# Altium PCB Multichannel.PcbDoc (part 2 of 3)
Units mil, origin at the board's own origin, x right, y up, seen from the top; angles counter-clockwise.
Board outline 3858.27 x 3228.35 mil, 2 copper layers (Top Layer, Bottom Layer); 95 components, 49 nets, 285 pads, 121 vias.

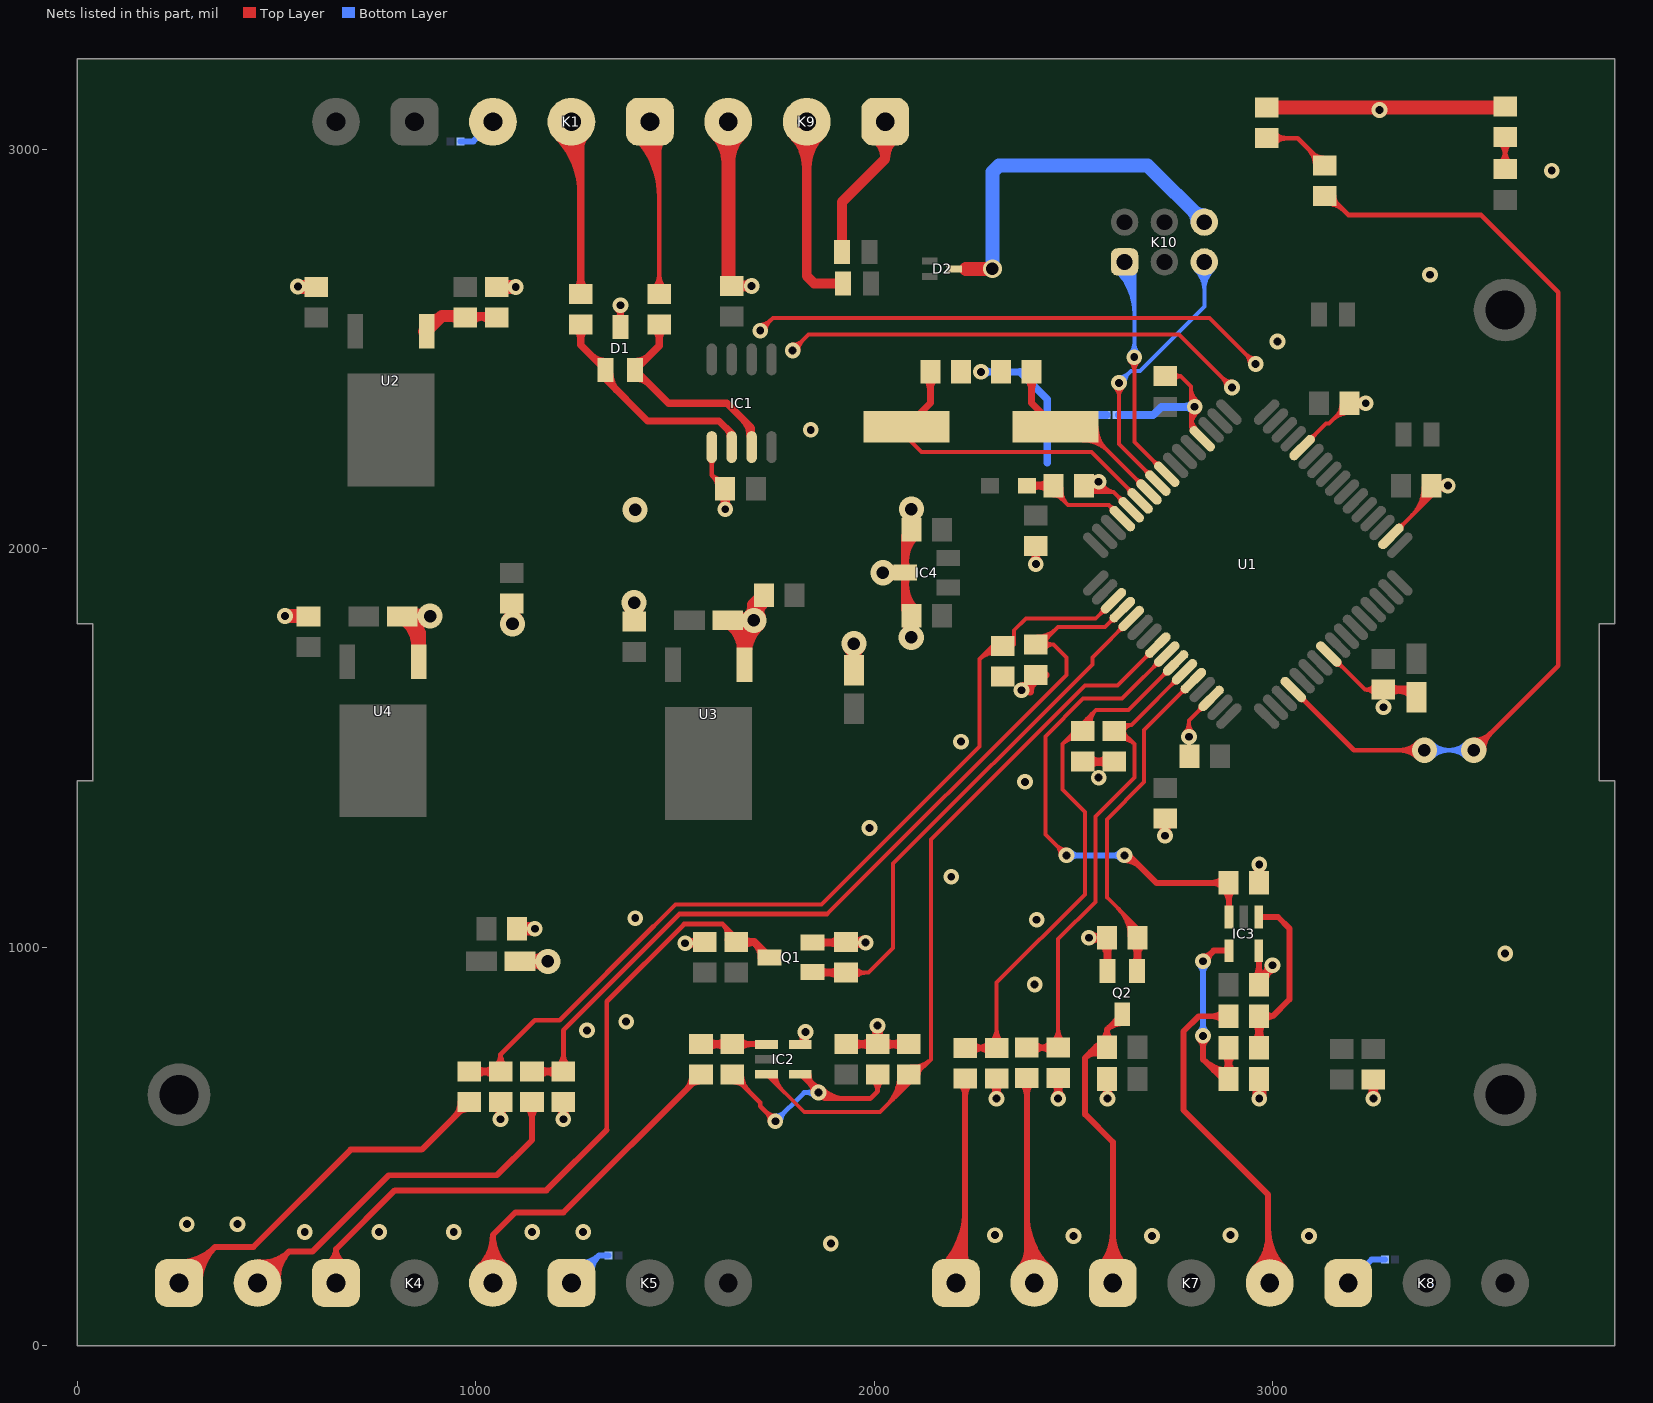
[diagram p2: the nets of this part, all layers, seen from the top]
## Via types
v1: diameter 39.37, hole 19.68, Top Layer to Bottom Layer, 99 vias
v2: diameter 62.99, hole 31.5, Top Layer to Bottom Layer, 21 vias
v3: diameter 47.24, hole 31.5, Top Layer to Bottom Layer, 1 vias

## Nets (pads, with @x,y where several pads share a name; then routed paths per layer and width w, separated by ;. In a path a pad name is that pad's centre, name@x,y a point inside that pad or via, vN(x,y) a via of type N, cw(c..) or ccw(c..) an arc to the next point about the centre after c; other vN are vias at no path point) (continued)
GND: C1.2 C2.2 C3.2 C4.2 C5.2 C6.2 C7.2 C8.2 C9.2 C10.2 C11.2 C12.2 C13.2 C14.2 C15.2 C16.2 C17.2 C18.2 C19.2 C20.2 C21.2 C22.2 C24.2 C26.2 C27.2 C28.2 C29.2 C30.2 C31.2 C32.2 D1.3 D2.3 IC1.5 IC2.5 IC3.5 IC4.3 K1.3 K5.1 K8.1 K9.3 K10.6 LED1.K LED2.K NT1.2 NT2.2 NT3.2 NT4.2 Q1.S Q2.S R4.1 R6.1 R8.1 R10.1 R14.1 R15.1 R16.1 R19.2 R20.1 R23.2 R26.2 R27.2 R29.2 U1.14 U1.24 U1.34 U1.44 U1.52 U1.60 U3.1 U4.1 | length 16822.6
  Top Layer w10: D1.3@1352.62,2576.98 ccw(c1327.02,2602.59) 1363.23,2602.59 ccw(c1399.44,2602.59) D1.3@1373.84,2576.98 ; v1@1352.85,2600.26 cw(c1327.78,2575.19) 1363.23,2575.19 cw(c1398.68,2575.19) v1@1373.61,2600.26 ; v1@1355.32,2598.27 cw(c1350.28,2590.39) 1359.31,2587.97 cw(c1371.34,2584.75) v1@1367.62,2596.63 ; v1@1358.84,2596.63 cw(c1355.12,2584.75) 1367.15,2587.97 cw(c1376.18,2590.39) v1@1371.14,2598.27 ; D1.3@1363.23,2556.38 v1(1363.23,2610.64) ; v1(1713.86,2546.82) 1746.09,2579.04 2840.7,2579.04 v1(2956.73,2463.01) ; v1@1713.86,2561.5 ccw(c1713.86,2596.96) 1738.93,2571.89 ccw(c1764,2546.82) v1@1728.54,2546.82 ; v1(1795.32,2496.82) 1835.54,2537.04 2764.59,2537.04 v1(2897.68,2403.95) ; v1@1795.32,2511.5 ccw(c1795.32,2546.96) 1820.39,2521.89 ccw(c1845.45,2496.82) v1@1810,2496.82 ; v2(2021.69,1939.47) IC4.3@2077.69,1939.47 ; v2@2034.45,1929.01 cw(c2056.56,1910.87) 2056.56,1939.47 cw(c2056.56,1968.06) v2@2034.45,1949.93 ; v2@2042.18,1922.66 cw(c2077.69,1893.54) IC4.3@2077.69,1939.47 ; v2@2042.18,1956.27 ccw(c2077.69,1985.39) IC4.3@2077.69,1939.47 ; IC4.3@2057.09,1928.86 ccw(c2031.48,1903.25) 2031.48,1939.47 ccw(c2031.48,1975.68) IC4.3@2057.09,1950.07 ; v2@2076.03,1797.64 ccw(c2050.67,1828.48) C11.2@2090.59,1828.48 ; C12.2@2078.04,2077.18 cw(c2057.29,2047.74) C12.2@2093.31,2047.73 ; C11.2@2079.1,1812.56 cw(c2051.35,1784.81) v2@2090.59,1784.81 ; C12.2@2079.5,2066.77 ccw(c2049.18,2098.83) v2(2093.31,2098.83) ; v2@2083.8,2085.35 cw(c2070.88,2067.02) 2093.31,2067.02 cw(c2115.73,2067.02) v2@2102.81,2085.35 ; v2@2090.59,1779.36 cw(c2131.15,1779.36) C11.2@2105.85,1811.06 ; v2@2090.59,1800.14 cw(c2114.56,1800.14) C11.2@2099.61,1818.88 ; C11.2@2090.59,1810.64 ccw(c2113.32,1810.64) v2@2101.46,1791.25 ; v2(2092.86,1777.18) 2090.59,1779.44 C11.2@2090.59,1828.48 ; C11.2@2093.31,1831.2 C11.2@2090.59,1828.48 ; v2@2094.3,2098.83 v2(2093.31,2098.83) ; v2@2106.68,1799.78 cw(c2124.24,1828.48) C11.2@2090.59,1828.48 ; C12.2@2107.12,2066.77 cw(c2137.44,2098.83) v2(2093.31,2098.83) ; C12.2@2108.57,2077.18 ccw(c2129.33,2047.74) C12.2@2093.31,2047.73 ; R26.2@2292.62,656.06 cw(c2258.31,621.75) 2306.84,621.75 cw(c2355.36,621.75) R26.2@2321.05,656.06 ; v1@2296.45,630.46 ccw(c2271.38,655.53) 2306.84,655.53 ccw(c2342.29,655.53) v1@2317.22,630.46 ; v1@2296.52,630.53 ccw(c2285.85,641.35) 2300.53,645.29 ccw(c2316.11,649.46) v1@2311.25,634.08 ; v1@2302.42,634.08 ccw(c2297.56,649.46) 2313.14,645.29 ccw(c2327.82,641.35) v1@2317.15,630.53 ; v1(2306.84,620.08) R26.2@2306.84,670.28 ; C1.2@2391.82,1991.02 cw(c2365.96,1961.04) v1(2405.55,1961.04) ; C1.2@2394.73,1996.01 C1.2@2404.95,2006.23 2405.55,2005.63 v1(2405.55,1961.04) ; v1@2395.17,1971.42 ccw(c2370.1,1996.49) 2405.55,1996.49 ccw(c2441.01,1996.49) v1@2415.94,1971.42 ; v1@2397.4,1973.25 ccw(c2393.53,1979.03) 2400.25,1980.83 ccw(c2406.96,1982.63) v1@2406.51,1975.69 ; v1@2403.77,1975.61 ccw(c2402.7,1984.34) 2411.19,1982.06 ccw(c2419.67,1979.79) v1@2414.39,1972.77 ; C1.2@2418.74,1991.62 ccw(c2447.6,1961.04) v1(2405.55,1961.04) ; R29.2@2447.15,657.05 cw(c2412.84,622.74) 2461.36,622.74 cw(c2509.88,622.74) R29.2@2475.57,657.05 ; v1@2450.98,630.46 ccw(c2425.91,655.53) 2461.36,655.53 ccw(c2496.82,655.53) v1@2471.75,630.46 ; v1@2451.02,630.51 ccw(c2439.88,641.75) 2455.17,645.85 ccw(c2471.96,650.35) v1@2466.22,633.94 ; v1@2456.51,633.94 ccw(c2450.76,650.35) 2467.55,645.85 ccw(c2482.84,641.75) v1@2471.7,630.51 ; v1(2461.36,620.08) R29.2@2461.36,671.26 ; C20.2@2526.04,2153.53 ccw(c2553.17,2179.65) 2553.17,2141.99 ; C20.2@2532.34,2164.26 C20.2@2525.97,2157.89 2541.86,2141.99 2600.2,2141.99 ; C20.2@2533.24,2160.46 ccw(c2576.68,2202.3) 2576.68,2141.99 ; C20.2@2540.44,2167.4 ccw(c2600.19,2224.95) 2600.19,2141.99 ; C20.2@2547.95,2164.89 ccw(c2573.46,2169.71) 2566.8,2144.61 ; v1@2558.14,2165.57 ccw(c2586.62,2178.26) 2577.62,2148.41 ; v1@2567.28,2169.64 ccw(c2612.99,2190.01) 2598.53,2142.1 ; C30.2@2571.22,649.19 cw(c2547.83,620.06) v1(2585.19,620.08) cw(c2628.08,620.06) C30.2@2597.93,650.57 ; v1@2574.81,630.46 ccw(c2549.74,655.53) 2585.19,655.53 ccw(c2620.64,655.53) v1@2595.57,630.46 ; v1@2583.15,634.62 ccw(c2581.85,643.94) 2590.94,641.51 ccw(c2600.03,639.07) v1@2594.23,631.65 ; C30.2@2583.8,669.29 2585.19,667.91 v1(2585.19,620.08) ; U1.60@2617.75,2117.63 ccw(c2601.3,2117.63) 2612.93,2129.26 ccw(c2624.56,2140.89) U1.60@2624.56,2124.44 ; U1.60@2644.74,2097.45 2600.2,2141.99 ; C16.2@2730.36,2432.49 2768.15,2432.49 ; C16.2@2752.55,2423.1 cw(c2768.15,2414.85) 2768.15,2432.49 ; C16.2@2752.55,2441.89 ccw(c2768.15,2450.14) 2768.15,2432.49 ; v1@2779.03,1538.35 ccw(c2753.96,1563.42) 2789.41,1563.42 ccw(c2824.86,1563.42) v1@2799.79,1538.35 ; v1(2789.41,1527.97) 2789.41,1568.42 U1.14@2845.18,1624.19 ; 2794.36,2304.66 cw(c2845.89,2304.66) v1@2813.08,2344.4 ; 2794.36,2308.31 ccw(c2815.23,2308.31) U1.52@2800.47,2293.55 ; 2794.36,2325.89 cw(c2828.37,2325.89) v1@2806.71,2352.11 ; 2794.36,2332.45 ccw(c2839.37,2332.45) U1.52@2807.54,2300.62 ; 2794.36,2385.27 ccw(c2827.75,2385.27) v1@2806.68,2359.36 ; U1.52@2796.23,2297.85 ccw(c2788.98,2300.15) 2794.36,2305.53 ; U1.52@2802.23,2302.59 cw(c2801.5,2312.67) 2794.36,2305.53 ; v1@2812.99,2367.12 cw(c2844.84,2406.29) 2794.36,2406.29 ; U1.14@2818.19,1604 cw(c2801.74,1604) 2813.37,1592.38 cw(c2825,1580.75) U1.14@2825,1597.19 ; U1.52@2824.3,2274.23 2824.3,2275.58 2794.36,2305.53 ; v1@2882.99,2403.95 ccw(c2847.54,2403.95) 2872.61,2429.02 ccw(c2897.68,2454.09) v1@2897.68,2418.64 ; v1@2942.05,2463.01 ccw(c2906.6,2463.01) 2931.66,2488.08 ccw(c2956.73,2513.14) v1@2956.73,2477.69 ; U1.44@3073.46,2253.35 3133.61,2313.5 3140.88,2313.5 C17.2@3191.97,2364.58 v1(3233,2364.58) ; U1.44@3093.64,2280.34 ccw(c3093.64,2296.78) 3105.27,2285.16 ccw(c3116.9,2273.53) U1.44@3100.45,2273.53 ; U1.24@3140.27,1735.54 3141.87,1735.54 3231.34,1646.08 ; 3150.1,2322.71 cw(c3191.97,2280.84) C17.2@3191.97,2340.05 ; U1.24@3160.46,1708.55 cw(c3160.46,1688.24) 3174.82,1702.6 ; 3160.79,2333.4 ccw(c3134.04,2360.15) C17.2@3171.87,2360.15 ; C17.2@3167.17,2339.78 cw(c3191.97,2314.98) C17.2@3191.97,2350.05 ; U1.24@3167.27,1715.36 ccw(c3179.84,1715.36) 3170.95,1706.47 ; C17.2@3207.85,2352.26 cw(c3233,2332.75) v1(3233,2364.58) ; C17.2@3207.85,2376.9 ccw(c3233,2396.41) v1(3233,2364.58) ; v1@3222.62,2354.2 ccw(c3197.55,2329.13) 3197.55,2364.58 ccw(c3197.55,2400.03) v1@3222.62,2374.97 ; C19.2@3256.06,1633.87 ccw(c3231.34,1614.96) 3231.34,1646.08 ; C19.2@3256.06,1658.29 cw(c3231.34,1677.2) 3231.34,1646.08 ; C19.2@3276.45,1646.08 3231.34,1646.08 ; U1.34@3296.17,2030.64 3296.46,2030.64 3397.93,2132.11 C15.2@3397.93,2157.89 v1(3439.02,2157.89) ; U1.34@3316.35,2057.63 ccw(c3316.35,2074.77) 3328.47,2062.65 ; U1.34@3323.16,2050.82 cw(c3338.91,2050.82) 3327.78,2061.95 ; 3348.52,2082.7 ccw(c3277.76,2153.46) C15.2@3377.83,2153.46 ; 3365.59,2099.77 ccw(c3311.9,2153.46) C15.2@3387.83,2153.46 ; 3382.66,2116.84 ccw(c3346.04,2153.46) C15.2@3397.83,2153.46 ; C15.2@3413.8,2145.55 cw(c3439.02,2125.94) v1(3439.02,2157.89) ; C15.2@3413.8,2170.22 ccw(c3439.02,2189.83) v1(3439.02,2157.89) ; v1@3428.63,2147.5 ccw(c3403.56,2122.44) 3403.56,2157.89 ccw(c3403.56,2193.34) v1@3428.63,2168.27 ; C12.2@2093.31,2047.73 v2(2093.31,2098.83) ; 2768.15,2432.49 2794.36,2406.29 ; 2794.36,2305.53 2794.36,2406.29
  Top Layer w12: IC1.5@1587.41,2222.63 cw(c1575.46,2210.68) 1592.36,2210.68 cw(c1609.26,2210.68) IC1.5@1597.31,2222.63 ; IC1.5@1592.36,2254.58 1592.36,2183.91 ; 1596.7,2179.57 cw(c1571.66,2154.53) C26.2@1607.07,2154.53 ; C26.2@1612.67,2132.17 cw(c1580.06,2099.56) 1626.17,2099.56 cw(c1672.28,2099.56) C26.2@1639.67,2132.17 ; v1@1616.42,2108.44 ccw(c1606.14,2118.56) 1620.08,2122.3 ccw(c1634.41,2126.14) v1@1630.12,2111.93 ; v1@1616.49,2108.51 ccw(c1593.13,2131.87) 1626.17,2131.87 ccw(c1659.21,2131.87) v1@1635.85,2108.51 ; v1@1622.22,2111.93 ccw(c1617.93,2126.14) 1632.26,2122.3 ccw(c1646.2,2118.56) v1@1635.92,2108.44 ; C26.2@1623.54,2173.45 cw(c1618.46,2210) 1592.37,2183.9 ; v1(1626.17,2098.83) C26.2@1626.17,2150.1 1592.36,2183.91
  Top Layer w15: R19.2@1050.15,598.78 cw(c1020.11,568.73) 1062.6,568.73 cw(c1105.09,568.73) R19.2@1075.04,598.78 ; v1@1053.68,576.59 ccw(c1043.4,586.15) 1056.96,589.78 ccw(c1070.78,593.49) v1@1066.36,579.88 ; v1@1053.98,576.91 ccw(c1033.18,597.71) 1062.6,597.71 ccw(c1092.02,597.71) v1@1071.21,576.91 ; v1@1058.84,579.88 ccw(c1054.42,593.49) 1068.24,589.78 ccw(c1081.8,586.15) v1@1071.52,576.59 ; v1(1062.6,568.29) R19.2@1062.6,611.22 ; R23.2@1207.64,598.78 cw(c1177.59,568.73) 1220.08,568.73 cw(c1262.57,568.73) R23.2@1232.52,598.78 ; v1@1211.16,576.59 ccw(c1200.88,586.15) 1214.44,589.78 ccw(c1228.26,593.49) v1@1223.84,579.88 ; v1@1211.46,576.91 ccw(c1190.66,597.71) 1220.08,597.71 ccw(c1249.5,597.71) v1@1228.7,576.91 ; v1@1216.32,579.88 ccw(c1211.9,593.49) 1225.72,589.78 ccw(c1239.28,586.15) v1@1229,576.59 ; v1(1220.08,568.29) R23.2@1220.08,611.22 ; v1@1534.08,1018.58 ccw(c1543.01,1027.78) 1546.33,1015.4 ccw(c1549.64,1003.02) v1@1537.31,1006.52 ; v1@1534.21,1001.23 cw(c1555.01,980.43) 1555.01,1009.84 cw(c1555.01,1039.26) v1@1534.21,1018.46 ; v1@1535.02,1009.84 cw(c1535.02,977.44) C29.2@1557.93,1000.35 ; v1@1535.33,1002.52 cw(c1544.25,995.82) 1547.14,1006.59 cw(c1551.47,1022.77) v1@1536.49,1015.29 ; C29.2@1557.03,1024.27 cw(c1525.59,1051.31) v1(1525.59,1009.84) 1571.85,1009.84 C29.2@1574.8,1012.8 ; v1@1817.13,780.87 cw(c1800.17,770.11) IC2.5@1814.37,755.91 v1@1827.42,768.95 ; v1@1827.42,775.21 ccw(c1851.39,775.21) IC2.5@1834.44,758.26 ; v1(1827.42,787.4) v1@1827.42,768.95 ; IC2.5@1833.6,758.87 cw(c1838.73,768.95) v1@1827.42,768.95 ; C21.2@2523.27,1465.17 C21.2@2523.27,1465.76 ; v1(2538.43,1023.62) R20.1@2583.8,1023.62 ; v1@2546.69,1014.66 cw(c2557.27,1003.19) 2561.31,1018.27 cw(c2565.88,1035.31) v1@2549.64,1028.4 ; v1@2546.69,1032.58 ccw(c2557.27,1044.06) 2561.31,1028.98 ccw(c2565.88,1011.93) v1@2549.64,1018.85 ; v1@2547.04,1015.01 cw(c2567.84,994.2) 2567.84,1023.62 cw(c2567.84,1053.04) v1@2547.04,1032.24 ; R20.1@2571.36,1011.18 ccw(c2541.32,981.14) 2541.32,1023.62 ccw(c2541.32,1066.11) R20.1@2571.36,1036.07 ; C28.2@2953.25,922.39 ccw(c2925.58,950.05) 2964.71,950.05 ; R10.1@2953.42,1178.46 ccw(c2925.12,1207.53) v1(2965.69,1207.54) ; v1@2962.59,1195.75 cw(c2959.53,1184.14) 2971.13,1187.25 cw(c2982.73,1190.36) v1@2974.27,1198.88 ; v1@2962.6,1210.63 v1(2965.69,1207.54) ; 2964.71,954.8 ccw(c3010.56,954.8) C28.2@2978.14,922.39 ; IC3.5@2964.71,991.14 2964.71,906.5 C28.2@2965.69,905.51 2965.69,921.34 v1(2999.08,954.72) ccw(c3037.8,916) C28.2@2983.23,911.41 ; R10.1@2965.69,1161.42 v1(2965.69,1207.54) ; v1@2968.8,1195.75 ccw(c2971.86,1184.14) 2960.26,1187.25 ccw(c2948.66,1190.36) 2957.11,1198.88 cw(c2936.28,1178.12) 2965.69,1178.12 cw(c2995.11,1178.12) v1@2974.31,1198.92 ; R10.1@2977.97,1178.46 cw(c3006.27,1207.53) v1(2965.69,1207.54) ; v1@2986.89,954.72 cw(c2957.48,954.72) 2978.28,933.92 cw(c2999.08,913.12) v1@2999.08,942.54 ; v1@2987.4,951.26 cw(c2961.62,943.62) 2984.9,930.17 cw(c3008.18,916.73) v1@3001.92,942.88 ; R27.2@3239.67,655.47 cw(c3209.48,625.29) v1@3252.17,625.29 ; v1@3243.15,628.27 ccw(c3230.35,639.9) 3247.05,644.37 ccw(c3267.91,649.96) v1@3257.85,630.86 ; v1@3243.55,628.69 ccw(c3222.75,649.5) 3252.17,649.5 ccw(c3281.59,649.5) v1@3260.79,628.69 ; v1@3246.46,630.84 ccw(c3236.33,649.93) 3257.2,644.33 ccw(c3273.71,639.91) v1@3261.13,628.33 ; v1(3252.17,620.08) R27.2@3252.17,667.86 ; v1@3252.17,625.57 cw(c3294.45,625.57) R27.2@3264.55,655.47
  Top Layer w19.68: v1@2369.5,1654.46 ccw(c2369.5,1686.58) C14.2@2392.21,1663.87 ; v1@2370.16,1654.44 ccw(c2371.9,1680.51) C14.2@2390.38,1662.03 ; 2390.38,1640.84 cw(c2421.91,1640.84) C14.2@2407.49,1668.88 ; 2390.38,1642.09 C14.2@2390.38,1662.03 ; C14.2@2429.36,1682.45 2410.79,1682.45 C14.2@2390.38,1662.03
  Top Layer w20: R6.1@1642.36,2658.87 v1(1692.36,2658.87) ; R6.1@1657.47,2648.2 cw(c1683.24,2622.42) 1683.24,2658.87 cw(c1683.24,2695.32) R6.1@1657.47,2669.55 ; R6.1@1668.97,2655.05 cw(c1674,2636.28) v1@1686.26,2651.36 ; R6.1@1668.97,2662.7 ccw(c1674,2681.47) v1@1686.26,2666.39 ; v1@1685.52,2652.02 ccw(c1668.98,2635.49) 1668.98,2658.87 ccw(c1668.98,2682.25) v1@1685.52,2665.72 ; Q1.S@1845.34,1011.41 v1(1978.35,1011.41) ; Q1.S@1862.41,1004.34 cw(c1879.48,987.27) 1879.48,1011.41 cw(c1879.48,1035.55) Q1.S@1862.41,1018.48 ; 1884.91,1011.41 ccw(c1884.91,1052.59) R16.1@1914.03,1023.47 ; 1891.6,1011.41 cw(c1891.6,979.69) R16.1@1914.03,1002.12 ; C27.2@1929.53,756.89 R8.1@2008.27,756.89 ; R16.1@1944.24,1002.12 cw(c1966.67,979.69) v1@1966.67,1011.41 ; R16.1@1944.24,1023.47 ccw(c1973.36,1052.59) v1@1973.36,1011.41 ; C27.2@1944.63,746.21 cw(c1970.41,720.44) 1970.41,756.89 cw(c1970.41,793.34) C27.2@1944.63,767.57 ; R16.1@1954.93,1016.35 ccw(c1960.58,1037.42) v1@1972.88,1019.41 ; R16.1@1955.87,1008.52 cw(c1960.14,992.56) v1@1971.62,1004.44 ; R16.1@1958.44,1015.41 cw(c1953.53,997.08) v1@1969.96,1006.57 ; v1@1971.5,1004.56 ccw(c1954.96,988.03) 1954.96,1011.41 ccw(c1954.96,1034.79) v1@1971.5,1018.26 ; R8.1@1993.16,746.21 ccw(c1967.39,720.44) 1967.39,756.89 ccw(c1967.39,793.34) R8.1@1993.16,767.57 ; R8.1@1997.59,767.57 ccw(c1971.82,793.34) 2008.27,793.34 ccw(c2044.72,793.34) R8.1@2018.94,767.57 ; v1@2000.75,797.18 cw(c1985.25,784.59) R8.1@2004.54,779.42 ; v1@2001.42,796.43 cw(c1984.89,779.9) 2008.27,779.9 cw(c2031.65,779.9) v1@2015.12,796.43 ; v1(2008.27,803.28) R8.1@2008.27,756.89 ; R8.1@2012,779.42 cw(c2031.28,784.59) v1@2015.79,797.18 ; R8.1@2023.37,746.21 cw(c2049.15,720.44) 2049.15,756.89 cw(c2049.15,793.34) R8.1@2023.37,767.57 ; IC4.3@2070.62,1932.4 cw(c2053.55,1915.32) 2077.69,1915.32 cw(c2101.84,1915.32) IC4.3@2084.77,1932.4 ; IC4.3@2070.62,1946.54 ccw(c2053.55,1963.61) 2077.69,1963.61 ccw(c2101.84,1963.61) IC4.3@2084.77,1946.54 ; R4.1@2071.9,746.21 ccw(c2046.13,720.44) 2046.13,756.89 ccw(c2046.13,793.34) R4.1@2071.9,767.57 ; 2077.69,1861.49 ccw(c2119.17,1861.49) C11.2@2089.84,1832.16 ; 2077.69,1909.77 ccw(c2167.46,1909.77) C11.2@2103.98,1846.3 ; 2077.69,1969.16 cw(c2167.46,1969.16) C12.2@2103.98,2032.63 ; 2077.69,2017.44 cw(c2119.17,2017.44) C12.2@2089.84,2046.77 ; R4.1@2087.01,756.89 R8.1@2008.27,756.89 ; C11.2@2093.31,1831.2 2077.69,1846.81 IC4.3@2077.69,1939.47 2077.69,2032.12 C12.2@2093.31,2047.73 ; C21.2@2523.27,1465.17 2523.66,1464.78 2601.03,1464.78 C24.2@2602.01,1465.76 ; C20.2@2536.64,2172.99 ccw(c2557.72,2194.07) v1@2557.72,2164.26 ; C20.2@2538.16,2153.41 cw(c2559.53,2137.79) v1@2559.53,2164.26 ; C21.2@2538.37,1455.09 cw(c2561.77,1431.69) 2561.77,1464.78 ; C21.2@2538.37,1476.44 ccw(c2566.53,1504.59) 2566.53,1464.78 ; v1@2555.98,2174.4 cw(c2532.34,2196.88) 2532.34,2164.26 v1@2559.53,2164.26 ; 2558.75,1464.78 ccw(c2558.75,1504.59) C24.2@2586.9,1476.44 ; v1(2563,2167.73) v1@2559.53,2164.26 ; 2563.51,1464.78 cw(c2563.51,1431.69) C24.2@2586.9,1455.09 ; R20.1@2573.13,1008.52 cw(c2544.01,979.4) 2585.19,979.4 ; Q2.S@2578.12,956.9 ccw(c2561.05,973.97) 2585.19,973.97 ccw(c2609.33,973.97) Q2.S@2592.26,956.9 ; R20.1@2583.8,1023.62 2585.19,1022.24 Q2.S@2585.19,939.83 ; 2585.19,986.09 cw(c2616.91,986.09) R20.1@2594.48,1008.52 ; C22.2@2719.29,1311.58 cw(c2694.46,1286.76) v1@2729.57,1286.76 ; v1@2722.22,1285.8 ccw(c2709.39,1296.79) C22.2@2725.71,1301.16 ; v1@2722.72,1286.34 ccw(c2706.19,1302.87) 2729.57,1302.87 ccw(c2752.95,1302.87) v1@2736.42,1286.34 ; v1@2724.73,1287.88 ccw(c2715.41,1304.02) C22.2@2733.41,1299.2 ; v1(2729.57,1279.49) C22.2@2729.57,1329.69 ; v1@2729.57,1284.86 cw(c2767.36,1284.86) C22.2@2740.64,1311.58 ; C22.2@2734.01,1301.43 ccw(c2751.77,1296.67) v1@2737.23,1285.42 ; C19.2@3276.45,1646.08 3341.58,1646.08 C5.2@3360.28,1627.38 ; C19.2@3291.56,1635.4 cw(c3317.33,1609.63) 3317.33,1646.08 cw(c3317.33,1682.53) C19.2@3291.56,1656.75 ; 3313.13,1646.08 cw(c3313.13,1594.01) C5.2@3349.95,1630.83
  Top Layer w35: v1(521.65,1830.71) 579.72,1830.71 C9.2@580.71,1829.72 ; v1@555.04,2656.5 C2.2@600.39,2656.5 ; C32.2@824.7,1824.7 cw(c745.56,1745.56) U4.1@857.48,1745.56 ; C32.2@827.27,1823.05 cw(c811.37,1779.77) 857.48,1779.77 ; C32.2@836.83,1829.72 ccw(c887.25,1829.72) 851.6,1794.07 ; C32.2@848.38,1832.22 cw(c848.38,1793.27) v2@875.93,1820.81 ; U4.1@857.48,1715.76 857.48,1788.19 C32.2@815.94,1829.72 818.44,1832.22 884.31,1832.22 v2(885.83,1830.71) ; R15.1@1053.15,2656.5 v1(1100.77,2656.5) ; v2@1082.62,1820.92 ccw(c1058.73,1844.81) 1092.52,1844.81 ccw(c1126.31,1844.81) v2@1102.42,1820.92 ; C4.2@1090.68,1861.81 1092.52,1859.97 v2(1092.52,1811.02) ; C10.2@1104.06,1046.26 v1(1148.62,1046.26) ; C8.2@1111.22,964.57 v2(1181.1,964.57) ; v2@1171.21,954.67 ccw(c1147.31,930.78) 1147.31,964.57 ccw(c1147.31,998.36) v2@1171.21,974.46 ; v2@1387.74,1854.39 cw(c1363.85,1830.5) 1397.64,1830.5 cw(c1431.43,1830.5) v2@1407.53,1854.39 ; C6.2@1397.64,1816.88 v2(1397.64,1864.29) ; K9.3@1603.81,3040.81 cw(c1531.25,2968.26) 1633.86,2968.26 cw(c1736.46,2968.26) K9.3@1663.91,3040.81 ; R6.1@1633.86,2667.38 K9.3@1633.86,3070.87 ; 1633.86,2687.06 ccw(c1666.12,2687.06) R6.1@1643.31,2664.25 ; C31.2@1641.63,1814.86 cw(c1562.49,1735.72) U3.1@1674.41,1735.72 ; C31.2@1644.2,1813.21 cw(c1628.29,1769.93) 1674.41,1769.93 ; C31.2@1653.76,1819.88 ccw(c1704.18,1819.88) 1668.53,1784.23 ; U3.1@1674.41,1708.66 1674.41,1778.35 C31.2@1632.87,1819.88 v2(1698.23,1819.88) 1698.23,1858.29 C7.2@1723.43,1883.49 ; U3.1@1674.41,1728.59 cw(c1789.52,1728.59) v2@1708.13,1809.99 ; 1674.41,1772 cw(c1709.63,1772) v2@1701.47,1806.27 ; v2@1688.33,1809.99 ccw(c1664.44,1786.09) 1664.44,1819.88 ccw(c1664.44,1853.67) 1688.33,1829.78 ccw(c1664.44,1853.67) 1698.23,1853.67 ccw(c1732.02,1853.67) v2@1708.13,1829.78 ; v2@1691.84,1832.34 ccw(c1676.98,1861.33) 1708.45,1852.9 ; v2@1698.23,1814.74 cw(c1770.09,1814.74) C7.2@1727.89,1872.91 ; C7.2@1702.89,1862.95 cw(c1723.43,1842.42) C7.2@1723.43,1871.46 ; v2@1711.25,1825.01 cw(c1761.95,1844.96) C7.2@1723.43,1883.49 ; v2@1938.92,1751.91 cw(c1914.08,1727.07) C3.2@1949.21,1727.07 ; v2(1948.82,1761.81) 1949.21,1761.42 C3.2@1949.21,1694.69 ; C3.2@1949.21,1728.97 cw(c1981.66,1728.97) v2@1958.72,1751.91 ; 2230.7,2701.93 v3(2296.51,2701.93) ; v1(2965.98,620.08) R14.1@2965.98,669.01 ; LED2.K@2984.37,3106.25 LED1.K@3579.68,3106.25 ; 3247.96,3106.25 cw(c3247.96,3080.49) v1@3266.17,3098.71 ; v1@3269.26,3098.71 cw(c3287.48,3080.49) 3287.48,3106.25 ; 3552.66,3106.25 ccw(c3552.66,3134.84) LED1.K@3572.88,3114.62 ; 1673.71,1796.63 cw(c1696.95,1772.11) 1697.86,1805.89 ccw(c1696.95,1772.11) 1673.71,1796.63 ; 1673.71,1796.63 ccw(c1650.46,1821.16) 1684.24,1820.26 cw(c1650.46,1821.16) 1673.71,1796.63
  Bottom Layer w15: NT4.2@961.88,3021.65 994.09,3021.65 K1.3@1043.31,3070.87 ; K5.1@1240.16,157.48 1309.06,226.38 ; K5.1@1247.72,194.21 ccw(c1256.96,239.1) 1289.37,206.69 ccw(c1321.77,174.29) K5.1@1276.89,165.04 ; K5.1@1250.75,208.9 ccw(c1263.68,271.74) 1309.05,226.37 ; K5.1@1291.58,168.07 cw(c1354.42,181.01) 1309.05,226.38 ; NT1.2@1333.27,226.38 1309.06,226.38 ; K8.1@3188.98,157.48 3248.03,216.54 NT3.2@3281.54,216.54
  Bottom Layer w20: NT2.2@2614.08,2334.85 2699.81,2334.85 2720.69,2355.72 v1(2803.73,2355.72) ; v1@2796.88,2348.87 ccw(c2780.35,2332.34) 2780.35,2355.72 ccw(c2780.35,2379.1) v1@2796.88,2362.57
  Bottom Layer w35: v3(2296.51,2701.93) 2296.51,2945.18 2312.94,2961.61 2685.41,2961.61 K10.6@2827.95,2819.07 ; K10.6@2811,2819.07 ccw(c2770.09,2819.07) 2799.02,2848.01 ccw(c2827.95,2876.94) K10.6@2827.95,2836.02
  other v1: 1891.14,256.51 2500,275.59 2696.85,275.59 3090.55,275.59 2303.15,277.68 2893.7,277.68 571.09,285.43 757.87,285.43 944.88,285.43 1141.73,285.43 1269.68,285.43 275.59,305.12 402.52,305.12 1279.53,791.26 1377.5,813.32 2402.31,906.5 3582.68,984.25 2407.31,1068.9 1400.23,1072.83 2193.29,1176.72 1988.19,1299.21 2378.18,1414.79 2562.96,1425.41 2217.56,1515.75 3277.43,1601.92 2369.5,1644.62 1840.64,2297.89 3011.81,2519.68 554.06,2657.48 3394.28,2687.01 3699.55,2948.23 3267.72,3100.25
  other v2: 1400.23,2097.45
NetC20_1: C20.1 L1.1 U1.61 | length 508.9
  Top Layer w10: C20.1@2449.19,2133.36 cw(c2449.19,2103.47) 2470.33,2124.61 ; C20.1@2449.19,2157.89 2449.19,2145.74 2486,2108.93 ; C20.1@2459.28,2152.95 ccw(c2496.3,2151.06) 2470.09,2124.85 ; C20.1@2465.59,2157.16 C20.1@2465.59,2162.87 ; C20.1@2469.27,2152.44 ccw(c2526.58,2149.52) 2486,2108.93 ; U1.61@2595.48,2095.36 ccw(c2579.03,2095.36) 2590.66,2106.99 ccw(c2602.29,2118.61) U1.61@2602.29,2102.17 ; U1.61@2622.47,2075.18 2588.71,2108.93 2486,2108.93
  Top Layer w20: L1.1@2382.91,2157.89 C20.1@2449.19,2157.89 ; L1.1@2392.72,2151.04 cw(c2409.25,2134.51) 2409.25,2157.89 cw(c2409.25,2181.27) L1.1@2392.72,2164.74 ; C20.1@2438.52,2147.21 ccw(c2412.74,2121.44) 2412.74,2157.89 ccw(c2412.74,2194.34) C20.1@2438.52,2168.56
NetC23_1: C23.1 U1.58 U5.2 | length 766.4
  Top Layer w10: U5.2@2454.77,2305.53 U5.2@2545.43,2305.53 ; U5.2@2523.66,2271.16 cw(c2523.66,2183.15) 2585.89,2245.38 ; U5.2@2523.66,2281.16 cw(c2523.66,2217.29) 2568.82,2262.45 ; U5.2@2545.43,2285.84 U1.58@2689.28,2141.99 ; U5.2@2548.03,2305.53 ccw(c2601.83,2305.53) 2563.79,2267.48 ; U5.2@2558.03,2305.53 ccw(c2635.98,2305.53) 2580.86,2250.41 ; U1.58@2662.29,2162.17 ccw(c2645.85,2162.17) 2657.47,2173.8 ccw(c2669.1,2185.43) U1.58@2669.1,2168.98
  Top Layer w18: C23.1@2383.34,2427.51 cw(c2355.86,2400.03) 2394.73,2400.03 cw(c2433.59,2400.03) C23.1@2406.11,2427.51 ; C23.1@2394.73,2443.32 2394.73,2365.57 U5.2@2454.77,2305.53
NetC25_2: C25.2 U1.59 U5.1 | length 928.4
  Top Layer w10: U5.1@2080.75,2305.53 2080.75,2279.94 2118.15,2242.53 2545.36,2242.53 2667.01,2120.88 U1.59@2667.01,2119.72 ; 2634.38,2153.51 cw(c2620.77,2139.9) U1.59@2640.02,2139.9 ; 2637.19,2150.71 ccw(c2646.83,2160.35) U1.59@2646.83,2146.71
  Top Layer w18: U5.1@2080.75,2305.53 2140.79,2365.57 C25.2@2140.79,2443.32 ; C25.2@2129.41,2427.51 cw(c2101.92,2400.03) 2140.79,2400.03 cw(c2179.65,2400.03) C25.2@2152.17,2427.51
NetD1_1: D1.1 IC1.6 R1.1 | length 737.1
  Top Layer w18: R1.1@1252.44,2551.03 cw(c1224.96,2523.55) 1263.82,2523.55 cw(c1302.69,2523.55) R1.1@1275.2,2551.03 ; R1.1@1263.82,2562.42 1263.82,2510.79 D1.1@1326.23,2448.38 1326.23,2425.12 1431.14,2320.21 1610.56,2320.21 1642.36,2288.4 IC1.6@1642.36,2254.58 ; 1290.38,2484.23 ccw(c1326.23,2520.07) D1.1@1326.23,2469.38 ; D1.1@1337.23,2438.38 ccw(c1395.78,2438.38) 1354.38,2396.98 ; 1630.71,2300.06 cw(c1612.23,2281.58) IC1.6@1638.36,2281.58
NetD1_2: D1.2 IC1.7 R3.1 | length 728.5
  Top Layer w18: D1.2@1400.23,2427.38 cw(c1400.23,2376.68) 1436.08,2412.53 ; D1.2@1400.23,2469.38 ccw(c1400.23,2520.07) 1436.08,2484.23 ; R3.1@1449.29,2551.03 cw(c1421.81,2523.55) 1460.67,2523.55 cw(c1499.54,2523.55) R3.1@1472.05,2551.03 ; R3.1@1460.67,2562.42 1460.67,2508.82 D1.2@1400.23,2448.38 1484.03,2364.58 1630.68,2364.58 1692.36,2302.9 IC1.7@1692.36,2254.58 ; 1670.46,2324.8 cw(c1627.25,2281.58) IC1.7@1688.36,2281.58
NetIC2_1: IC2.1 R2.1 R7.2 | length 346
  Top Layer w15: R7.2@1644.09,756.89 1728.74,756.89 IC2.1@1729.72,755.91 ; R7.2@1660.97,744.45 cw(c1691.01,714.4) 1691.01,756.89 cw(c1691.01,799.38) R7.2@1660.97,769.33
  Top Layer w20: R2.1@1565.35,756.89 R7.2@1644.09,756.89 ; R2.1@1580.46,746.21 cw(c1606.23,720.44) 1606.23,756.89 cw(c1606.23,793.34) R2.1@1580.46,767.57 ; R7.2@1628.99,746.21 ccw(c1603.21,720.44) 1603.21,756.89 ccw(c1603.21,793.34) R7.2@1628.99,767.57
NetIC2_4: IC2.4 R7.1 R8.2 | length 1156.6
  Top Layer w12: R7.1@1644.09,680.12 1713.98,610.24 1713.98,601.18 v1(1751.97,563.19) ; R7.1@1648.52,661.02 cw(c1648.52,625.61) 1673.57,650.65 ; R7.1@1667.62,680.12 ccw(c1724.42,680.12) 1684.26,639.95 ; v1@1738.28,563.19 ccw(c1705.24,563.19) 1728.61,586.55 ccw(c1751.97,609.91) v1@1751.97,576.87 ; IC2.4@1814.37,681.1 v1(1860.24,635.24) 1875.39,620.08 ; IC2.4@1824.91,681.1 ccw(c1850.37,681.1) 1832.37,663.1 ; IC2.4@1836.91,681.1 ccw(c1891.34,681.1) v1@1852.85,642.62 ; 1838.12,668.15 ccw(c1874.72,689.28) v1@1863.78,648.46 ; 1844.64,656.85 cw(c1824.01,644.94) v1@1847.02,638.78 ; v1@1846.55,635.24 ccw(c1813.51,635.24) 1836.87,658.6 ccw(c1860.24,681.96) v1@1860.24,648.92 ; v1@1861.43,636.43 ccw(c1900.9,675.9) 1900.9,620.08 ; v1@1864.94,622.39 cw(c1868.36,613.05) 1875.39,620.08 ; v1@1869.91,644.91 ccw(c1929.87,704.87) 1929.87,620.08 ; v1@1873.09,630.53 ccw(c1882.43,627.11) 1875.39,620.08 ; R8.2@1995.89,665.57 cw(c1973.08,638.78) 2008.27,638.78 ; R8.2@2008.27,680.12 2008.27,638.78 ; R8.2@2020.65,665.57 ccw(c2043.45,638.78) 2008.27,638.78 ; 1875.39,620.08 1989.57,620.08 2008.27,638.78
  Bottom Layer w12: v1(1751.97,563.19) 1824.02,635.24 v1(1860.24,635.24) ; v1@1751.97,576.87 ccw(c1751.97,609.91) 1775.33,586.55 ccw(c1798.69,563.19) v1@1765.65,563.19 ; v1@1850.56,625.56 ccw(c1827.2,602.2) 1827.2,635.24 ccw(c1827.2,668.28) v1@1850.56,644.91
NetIC3_1: IC3.1 R9.1 R11.2 | length 598.5
  Top Layer w15: IC3.1@2964.71,1075.79 3012.94,1075.79 3041.34,1047.39 3041.34,868.72 2999.39,826.77 ; R9.1@2965.69,826.77 2999.39,826.77 ; R9.1@2980.14,816.72 cw(c2999.39,803.31) 2999.39,826.77 ; R9.1@2980.14,836.83 ccw(c2999.39,850.23) 2999.39,826.77
  Top Layer w20: R11.2@2955.02,763.14 ccw(c2929.24,788.91) 2965.69,788.91 ccw(c3002.14,788.91) R11.2@2976.37,763.14 ; R9.1@2955.02,811.67 cw(c2929.24,785.89) 2965.69,785.89 cw(c3002.14,785.89) R9.1@2976.37,811.67 ; R11.2@2965.69,748.03 R9.1@2965.69,826.77
NetIC3_4: IC3.4 R11.1 R14.2 | length 896
  Top Layer w15: v1@2816.25,768.94 cw(c2795.45,748.14) 2824.87,748.14 cw(c2854.28,748.14) v1@2833.48,768.94 ; v1(2824.87,777.56) 2824.87,718.5 2874.08,669.29 R14.2@2888.92,669.29 ; v1(2824.87,964.57) 2851.44,991.14 IC3.4@2889.91,991.14 ; v1@2824.87,976.75 ccw(c2824.87,1006.17) 2845.67,985.37 ccw(c2866.47,964.57) v1@2837.05,964.57 ; 2825.98,717.39 ccw(c2888.92,780.33) R14.2@2888.92,691.32 ; 2851.59,691.78 ccw(c2888.92,729.12) R14.2@2888.92,676.32
  Top Layer w20: R14.2@2878.25,684.4 ccw(c2852.47,710.17) 2888.92,710.17 ccw(c2925.37,710.17) R14.2@2899.6,684.4 ; R11.1@2878.25,732.93 cw(c2852.47,707.15) 2888.92,707.15 cw(c2925.37,707.15) R11.1@2899.6,732.93 ; R14.2@2888.92,669.29 R11.1@2888.92,748.03
  Bottom Layer w15: v1@2816.25,786.18 ccw(c2795.45,806.98) 2824.87,806.98 ccw(c2854.28,806.98) v1@2833.48,786.18 ; v1@2816.25,955.95 cw(c2795.45,935.15) 2824.87,935.15 cw(c2854.28,935.15) v1@2833.48,955.95 ; v1(2824.87,777.56) 2824.87,873.36 v1(2824.87,964.57)
NetK1_1: K1.1 R3.2 | length 1154.5
  Top Layer w12: K1.1@1398.82,3032.68 cw(c1249.51,2883.37) 1460.67,2883.37 ; K1.1@1407.31,3041.17 cw(c1278.48,2912.34) 1460.67,2912.34 ; K1.1@1415.79,3049.65 cw(c1307.45,2941.31) 1460.67,2941.31 ; K1.1@1424.28,3058.14 cw(c1336.42,2970.28) 1460.67,2970.28 ; K1.1@1432.77,3066.62 cw(c1365.4,2999.25) 1460.67,2999.25 ; K1.1@1437.01,3070.87 1460.67,3047.2 R3.2@1460.67,2639.19 ; R3.2@1447.17,2652.69 ccw(c1414.56,2685.3) 1460.67,2685.3 ccw(c1506.78,2685.3) R3.2@1474.18,2652.69 ; 1460.67,2997.63 cw(c1510.25,2997.63) K1.1@1475.19,3032.68
NetK1_2: K1.2 R1.2 | length 919.4
  Top Layer w18: K1.2@1204.1,3034.8 cw(c1059.91,2890.61) 1263.82,2890.61 ; K1.2@1216.82,3047.53 cw(c1103.36,2934.07) 1263.82,2934.07 ; K1.2@1229.55,3060.26 cw(c1146.82,2977.53) 1263.82,2977.53 ; K1.2@1236.22,3066.93 K1.2@1240.16,3070.87 1263.82,3047.2 R1.2@1263.82,2639.19 ; R1.2@1252.44,2650.57 ccw(c1224.96,2678.05) 1263.82,2678.05 ccw(c1302.69,2678.05) R1.2@1275.2,2650.57 ; 1263.82,3004.87 cw(c1306.16,3004.87) K1.2@1276.22,3034.8
NetK3_1: K3.1 R18.2 | length 1323.9
  Top Layer w15: K3.1@255.91,157.48 346.68,248.25 442.68,248.25 686.55,492.13 864.76,492.13 R18.2@983.86,611.22 ; K3.1@255.91,194.98 ccw(c255.91,285.51) 319.92,221.5 ccw(c383.94,157.48) K3.1@293.41,157.48 ; K3.1@255.91,209.98 ccw(c255.91,336.73) 345.53,247.1 ccw(c435.15,157.48) K3.1@308.41,157.48 ; 946.26,573.62 ccw(c908.65,611.22) R18.2@961.83,611.22 ; 956.95,584.31 cw(c979.43,561.83) R18.2@979.43,593.62
NetK3_2: K3.2 R22.2 | length 1276.5
  Top Layer w15: K3.2@452.76,157.48 531.5,236.22 ; K3.2@456.34,194.81 ccw(c462.61,260.11) 509,213.72 ccw(c555.38,167.34) K3.2@490.08,161.07 ; K3.2@457.77,209.74 ccw(c466.55,301.16) 531.49,236.22 ; K3.2@505.02,162.5 cw(c596.43,171.28) 531.49,236.22 ; R22.2@1128.89,598.78 cw(c1098.85,568.73) 1141.34,568.73 cw(c1183.83,568.73) R22.2@1153.78,598.78 ; R22.2@1141.34,611.22 1141.34,516.04 1053.15,427.85 781.71,427.85 590.08,236.22 531.5,236.22
NetK6_1: K6.1 R24.2 | length 1104.3
  Top Layer w15: K6.1@2167.6,194.6 ccw(c2021.56,340.65) 2228.09,340.65 ; K6.1@2178.21,184 ccw(c2057.77,304.43) 2228.09,304.43 ; K6.1@2188.81,173.39 ccw(c2093.98,268.22) 2228.09,268.22 ; K6.1@2199.42,162.78 ccw(c2130.2,232.01) 2228.09,232.01 ; K6.1@2204.72,157.48 2228.09,180.85 R24.2@2228.09,670.28 ; R24.2@2215.65,657.83 cw(c2185.61,627.79) 2228.09,627.79 cw(c2270.58,627.79) R24.2@2240.54,657.83 ; 2228.09,227.81 ccw(c2275.05,227.81) K6.1@2241.85,194.6
NetK6_2: K6.2 R28.2 | length 1067.9
  Top Layer w15: K6.2@2364.45,194.6 ccw(c2320.58,238.47) 2382.62,238.47 ; R28.2@2370.18,658.82 cw(c2340.14,628.77) 2382.62,628.77 cw(c2425.11,628.77) R28.2@2395.07,658.82 ; 2382.62,221.34 ccw(c2465.44,221.34) K6.2@2406.88,162.78 ; 2382.62,257.55 ccw(c2501.65,257.55) K6.2@2417.48,173.39 ; 2382.62,293.77 ccw(c2537.86,293.77) K6.2@2428.09,184 ; 2382.62,329.98 ccw(c2574.08,329.98) K6.2@2438.7,194.6 ; R28.2@2382.62,671.26 2382.62,176.43 K6.2@2401.57,157.48
NetK9_1: K9.1 R32.2 | length 476
  Top Layer w25: R32.2@1918.58,2766.91 1918.58,2868.97 2027.56,2977.95 ; K9.1@1999.74,3032.36 cw(c1960.44,2977.95) 2027.56,2977.95 ; K9.1@2027.56,3070.87 2027.56,2977.95 ; K9.1@2055.37,3032.36 ccw(c2094.68,2977.95) 2027.56,2977.95
NetK9_2: K9.2 R33.2 | length 666
  Top Layer w25: K9.2@1797.12,3037.28 cw(c1716.03,2956.19) 1830.71,2956.19 cw(c1945.38,2956.19) K9.2@1864.3,3037.28 ; K9.2@1830.71,3070.87 1830.71,2683.64 1849.42,2664.93 R33.2@1921.58,2664.93
NetLED1_A: LED1.A R5.1 | length 219.6
  Top Layer w12: R5.1@3569.17,2965.28 ccw(c3536.57,2997.88) 3582.68,2997.88 ccw(c3628.78,2997.88) R5.1@3596.18,2965.28 ; LED1.A@3569.17,3018.98 cw(c3536.57,2986.37) 3582.68,2986.37 cw(c3628.78,2986.37) LED1.A@3596.18,3018.98 ; R5.1@3582.68,2957.77 LED1.A@3582.68,3032.48
NetLED2_A: LED2.A R21.2 | length 318.5
  Top Layer w12: LED2.A@2984.37,3029.48 3062.06,3029.48 R21.2@3129.92,2961.61 ; LED2.A@3002.31,3015.98 cw(c3034.91,2983.37) 3034.91,3029.48 cw(c3034.91,3075.59) LED2.A@3002.31,3042.98 ; 3089.76,3001.78 cw(c3049.59,2961.61) R21.2@3106.39,2961.61 ; 3100.45,2991.09 ccw(c3125.49,3016.13) R21.2@3125.49,2980.71
NetQ1_G: Q1.G R16.2 U1.5 | length 1499.7
  Top Layer w10: R16.2@1929.13,936.02 1985.7,936.02 2047.24,997.57 2047.24,1209.59 2547.3,1709.65 2547.3,1727.19 U1.5@2644.74,1824.63 ; R16.2@1947.77,921.81 cw(c1982.08,887.5) 1982.08,936.02 cw(c1982.08,984.55) R16.2@1947.77,950.24 ; U1.5@2617.75,1804.44 cw(c2601.3,1804.44) 2612.93,1792.82 cw(c2624.56,1781.19) U1.5@2624.56,1797.63
  Top Layer w20: Q1.G@1845.34,937.41 1846.72,936.02 R16.2@1929.13,936.02 ; Q1.G@1862.41,930.34 cw(c1876.14,916.61) 1876.14,936.02 ; Q1.G@1862.41,944.48 ccw(c1882.83,964.9) 1882.83,936.02 ; R16.2@1914.03,925.35 ccw(c1888.25,899.57) 1888.25,936.02 ccw(c1888.25,972.47) R16.2@1914.03,946.7
NetQ2_G: Q2.G R20.2 U1.12 | length 1144.2
  Top Layer w10: 2612.04,1096.7 cw(c2543.39,1028.05) R20.2@2640.48,1028.05 ; 2629.11,1079.63 cw(c2577.53,1028.05) R20.2@2650.48,1028.05 ; 2646.18,1062.56 cw(c2611.68,1028.05) R20.2@2660.48,1028.05 ; R20.2@2660.57,1023.62 2660.57,1048.17 2583.5,1125.25 2583.5,1320.43 2677.17,1414.1 2677.17,1545.26 U1.12@2800.64,1668.73 ; U1.12@2773.64,1648.55 cw(c2757.2,1648.55) 2768.83,1636.92 cw(c2780.46,1625.29) U1.12@2780.46,1641.74
  Top Layer w20: R20.2@2649.9,1008.52 cw(c2624.12,982.74) 2660.57,982.74 cw(c2697.03,982.74) R20.2@2671.25,1008.52 ; Q2.G@2652.12,956.9 ccw(c2631.7,977.31) 2660.57,977.31 ; Q2.G@2659.19,939.83 2660.57,941.21 R20.2@2660.57,1023.62 ; 2660.57,970.62 ccw(c2679.99,970.62) Q2.G@2666.26,956.9
NetR12_1: R12.1 R15.2 U2.1 | length 400.9
  Top Layer w20: R12.1@969.09,2583.44 R15.2@1047.83,2583.44 ; R12.1@989.51,2569.05 cw(c1024.27,2534.3) R15.2@1024.27,2583.44 ; R12.1@989.51,2590.4 ccw(c1006.31,2607.2) 1006.31,2583.44 ; R12.1@992.29,2572.86 cw(c1006.99,2565.36) 1011.27,2581.31 ; R12.1@1003.29,2583.44 cw(c1003.29,2534.3) R15.2@1038.04,2569.05 ; 1021.25,2583.44 ccw(c1021.25,2607.2) R15.2@1038.04,2590.4
  Top Layer w30: U2.1@870.74,2544.41 ccw(c872.76,2552.09) U2.1@878.37,2546.48 ; U2.1@877.17,2545.28 915.33,2583.44 ; U2.1@878.35,2573.43 ccw(c888.12,2610.65) 915.33,2583.44 ; 936.62,2583.44 cw(c936.62,2546.37) R12.1@962.84,2572.58 ; R12.1@969.09,2583.44 915.33,2583.44
NetR21_1: R21.1 U1.20 | length 3161.1
  Top Layer w12: U1.20@3051.19,1646.46 3203.59,1494.06 v2(3379.96,1494.06) ; U1.20@3071.37,1620.46 cw(c3071.37,1606.44) 3081.29,1616.36 cw(c3091.21,1626.28) U1.20@3077.18,1626.28 ; R21.1@3134.35,2865.74 cw(c3134.35,2801.41) 3179.84,2846.9 ; R21.1@3134.35,2877.74 cw(c3134.35,2842.38) R21.1@3159.36,2867.39 ; R21.1@3135.92,2878.84 R21.1@3129.92,2884.84 3141.9,2884.84 3189.5,2837.24 3521.93,2837.24 3715.86,2643.31 3715.86,1705.98 v2(3503.94,1494.06) ; R21.1@3153.45,2884.84 ccw(c3181.33,2884.84) 3161.61,2865.13 ; v2@3361.93,1476.03 ccw(c3318.41,1432.51) 3318.41,1494.06 ccw(c3318.41,1555.61) v2@3361.93,1512.09 ; v2@3370.42,1484.52 ccw(c3347.38,1461.48) 3347.38,1494.06 ccw(c3347.38,1526.64) v2@3370.42,1503.6 ; v2@3503.94,1507.56 ccw(c3503.94,1540.14) 3526.98,1517.1 ccw(c3550.02,1494.06) v2@3517.43,1494.06 ; v2@3503.94,1519.56 ccw(c3503.94,1581.11) 3547.46,1537.58 ccw(c3590.99,1494.06) v2@3529.43,1494.06
  Bottom Layer w12: v2(3379.96,1494.06) v2(3503.94,1494.06) ; v2@3389.51,1484.52 cw(c3412.54,1461.48) 3412.54,1494.06 cw(c3412.54,1526.64) v2@3389.51,1503.6 ; v2@3397.99,1476.03 cw(c3441.51,1432.51) 3441.51,1494.06 cw(c3441.51,1555.61) v2@3397.99,1512.09 ; v2@3485.91,1476.03 ccw(c3442.38,1432.51) 3442.38,1494.06 ccw(c3442.38,1555.61) v2@3485.91,1512.09 ; v2@3494.39,1484.52 ccw(c3471.35,1461.48) 3471.35,1494.06 ccw(c3471.35,1526.64) v2@3494.39,1503.6
PDI_CLK: K10.5 U1.57 | length 1021.7
  Top Layer w10: v1@2603.7,2405.34 cw(c2578.63,2380.27) 2614.08,2380.27 cw(c2649.53,2380.27) v1@2624.47,2405.34 ; v1(2614.08,2415.72) 2614.08,2262.19 2712.95,2163.33 U1.57@2712.95,2162.87 ; 2679.42,2196.86 cw(c2667.01,2184.44) U1.57@2684.56,2184.44 ; 2680.53,2195.75 ccw(c2691.37,2206.59) U1.57@2691.37,2191.26
  Bottom Layer w10: v1(2614.08,2415.72) 2643.99,2445.63 2666.76,2445.63 2827.95,2606.82 K10.5@2827.95,2719.07 ; v1@2614.08,2430.41 ccw(c2614.08,2465.86) 2639.15,2440.79 ccw(c2664.22,2415.72) v1@2628.77,2415.72 ; K10.5@2807.13,2698.25 cw(c2756.86,2647.98) 2827.95,2647.98 cw(c2899.05,2647.98) K10.5@2848.78,2698.25 ; K10.5@2814.2,2705.32 cw(c2781,2672.12) 2827.95,2672.12 cw(c2874.91,2672.12) K10.5@2841.71,2705.32
PDI_DAT: K10.1 U1.56 | length 1132.8
  Top Layer w10: v1@2642.01,2469.93 cw(c2616.94,2444.86) 2652.39,2444.86 cw(c2687.85,2444.86) v1@2662.78,2469.93 ; v1(2652.39,2480.32) 2652.39,2267.96 U1.56@2735.22,2185.14 ; U1.56@2706.83,2206.72 ccw(c2690.39,2206.72) 2702.01,2218.34 ccw(c2713.64,2229.97) U1.56@2713.64,2213.53
  Bottom Layer w10: K10.1@2607.13,2698.25 cw(c2497.85,2588.97) 2652.39,2588.97 ; K10.1@2614.2,2705.32 cw(c2522,2613.12) 2652.39,2613.12 ; K10.1@2621.27,2712.39 cw(c2546.14,2637.26) 2652.39,2637.26 ; K10.1@2627.95,2719.07 2652.39,2694.63 v1(2652.39,2480.32) ; K10.1@2628.34,2719.46 cw(c2570.28,2661.4) 2652.39,2661.4 ; K10.1@2635.41,2726.53 cw(c2594.42,2685.54) 2652.39,2685.54 ; v1@2642.01,2490.7 ccw(c2616.94,2515.77) 2652.39,2515.77 ccw(c2687.85,2515.77) v1@2662.78,2490.7
PSU1_ADC_I: C14.1 R22.1 R23.1 U1.4 | length 2539.2
  Top Layer w10: 1881.84,1082.99 2482.29,1683.44 2482.29,1726.6 2449.67,1759.22 ; C14.1@2409.38,1769.32 ccw(c2409.38,1812.28) 2439.75,1781.9 ; C14.1@2409.38,1779.32 ccw(c2409.38,1846.42) 2456.82,1798.97 ; C14.1@2425.43,1747.13 cw(c2449.67,1728.88) 2449.67,1759.22 ; C14.1@2425.43,1771.31 ccw(c2449.67,1789.56) 2449.67,1759.22 ; C14.1@2429.47,1759.22 cw(c2459.42,1759.22) 2438.24,1780.39 ; U1.4@2595.48,1826.72 cw(c2579.03,1826.72) 2590.66,1815.09 cw(c2602.29,1803.46) U1.4@2602.29,1819.9 ; U1.4@2622.47,1846.9 2579.08,1803.51 2461.36,1803.51 2429.36,1771.51 2429.36,1759.22 2449.67,1759.22
  Top Layer w12: R23.1@1206.57,701.5 ccw(c1173.97,734.1) 1220.08,734.1 ccw(c1266.19,734.1) R23.1@1233.58,701.5 ; R23.1@1220.08,687.99 1220.08,791.8 1511.28,1082.99 1881.84,1082.99
  Top Layer w20: R22.1@1141.34,687.99 R23.1@1220.08,687.99 ; R22.1@1156.44,677.32 cw(c1182.22,651.54) 1182.22,687.99 cw(c1182.22,724.44) R22.1@1156.44,698.67 ; R23.1@1204.97,677.32 ccw(c1179.2,651.54) 1179.2,687.99 ccw(c1179.2,724.44) R23.1@1204.97,698.67
PSU1_ADC_V: C13.1 R18.1 R19.1 U1.3 | length 2614.2
  Top Layer w10: 1446.16,1051.89 1501.49,1107.23 1867.6,1107.23 2263.78,1503.42 2263.78,1722.44 ; 2276.47,1735.13 cw(c2306.38,1705.22) C13.1@2316.09,1746.39 ; 2289.15,1747.82 cw(c2311.22,1725.75) C13.1@2318.38,1756.12 ; C13.1@2313.79,1736.66 ccw(c2301.54,1684.69) 2263.78,1722.44 ; U1.3@2573.2,1848.99 cw(c2556.76,1848.99) 2568.39,1837.36 cw(c2580.02,1825.73) U1.3@2580.02,1842.18 ; U1.3@2600.2,1869.17 2555.66,1824.63 2380.13,1824.63 2350.62,1795.12 2350.62,1759.22 2300.56,1759.22 2263.78,1722.44
  Top Layer w12: R19.1@1049.82,702.18 ccw(c1023.94,730.9) 1062.6,730.9 ; R19.1@1062.6,687.99 1062.6,730.91 ; R19.1@1075.38,702.18 cw(c1101.26,730.9) 1062.6,730.9 ; 1446.16,1051.89 1211.19,816.93 1148.62,816.93 1062.6,730.91
  Top Layer w20: R18.1@983.86,687.99 R19.1@1062.6,687.99 ; R18.1@998.96,677.32 cw(c1024.74,651.54) 1024.74,687.99 cw(c1024.74,724.44) R18.1@998.96,698.67 ; R19.1@1047.49,677.32 ccw(c1021.72,651.54) 1021.72,687.99 ccw(c1021.72,724.44) R19.1@1047.49,698.67
PSU1_DAC0: IC2.3 R4.2 U1.8 | length 2288.7
  Top Layer w10: IC2.3@1729.72,681.1 1824.43,586.39 2014.94,586.39 2087.01,658.46 R4.2@2087.01,680.12 2103.27,680.12 2141.84,718.69 ; IC2.3@1733.27,681.1 ccw(c1741.82,681.1) IC2.3@1735.77,675.05 ; IC2.3@1743.27,681.1 ccw(c1775.97,681.1) 1752.84,657.98 ; IC2.3@1753.27,681.1 ccw(c1810.11,681.1) 1769.92,640.91 ; 2029.83,601.28 ccw(c1950.99,680.12) R4.2@2062.48,680.12 ; 2046.9,618.35 ccw(c1985.13,680.12) R4.2@2072.48,680.12 ; 2063.97,635.42 ccw(c2019.27,680.12) R4.2@2082.48,680.12 ; 2081.04,652.5 ccw(c2053.42,680.12) R4.2@2092.48,680.12 ; R4.2@2092.09,690.2 ccw(c2094.93,734.34) 2126.21,703.06 ; R4.2@2092.73,700.18 ccw(c2096.82,763.7) 2141.84,718.69 ; R4.2@2111.54,680.12 cw(c2131.5,680.12) 2117.38,694.23 ; U1.8@2684.56,1737.63 cw(c2668.12,1737.63) 2679.74,1726 cw(c2691.37,1714.38) U1.8@2691.37,1730.82 ; U1.8@2711.55,1757.81 2610.76,1657.02 2528.75,1657.02 2141.84,1270.1 2141.84,718.69
PSU1_ON/OFF: K4.1 Q1.D R13.1 | length 2071.4
  Top Layer w12: 1328.74,541.34 1328.74,863.75 1522.98,1057.99 1619.54,1057.99 ; R13.1@1630.61,1017.54 ccw(c1589.6,1028.05) 1619.54,1057.99 ; 1634.42,1043.11 cw(c1613.29,1021.98) R13.1@1642.24,1014.56 ; R13.1@1653.54,1012.8 1653.54,1023.99 1619.54,1057.99
  Top Layer w15: K4.1@626.17,204.46 ccw(c607.26,242.35) 649.61,242.35 ; K4.1@632.86,191.04 ccw(c619.36,218.1) 649.61,218.1 ccw(c679.85,218.1) K4.1@666.35,191.04 ; K4.1@649.61,157.48 649.61,242.35 ; K4.1@673.05,204.46 cw(c691.95,242.35) 649.61,242.35 ; 1328.74,541.34 1177.39,389.99 797.24,389.99 649.61,242.35
  Top Layer w20: R13.1@1653.54,1012.8 1698.95,1012.8 Q1.D@1737.34,974.41 ; R13.1@1668.65,1002.12 cw(c1694.42,976.34) 1694.42,1012.8 cw(c1694.42,1049.25) R13.1@1668.65,1023.47 ; 1703.2,1008.55 cw(c1669.05,974.41) Q1.D@1717.34,974.41
PSU1_OPAMP: K4.3 R2.2 | length 1190
  Top Layer w15: K4.3@1007.59,195.96 ccw(c931.62,277.83) 1043.31,277.83 ; K4.3@1017.8,184.97 ccw(c963.53,243.44) 1043.31,243.44 ccw(c1123.08,243.44) K4.3@1068.82,184.97 ; K4.3@1043.31,157.48 1043.31,277.83 ; K4.3@1079.02,195.96 cw(c1154.99,277.83) 1043.31,277.83 ; 1527.33,641.51 ccw(c1488.72,680.12) R2.2@1543.33,680.12 ; 1539.45,653.63 cw(c1560.93,632.15) R2.2@1560.93,662.52 ; R2.2@1552.81,680.12 R2.2@1565.35,680.12 ; R2.2@1556.1,670.28 1220.47,334.65 1100.12,334.65 1043.31,277.83
PSU2_ADC_I: C24.1 R28.1 R29.1 U1.11 | length 1622.1
  Top Layer w10: R29.1@2447.15,762.24 ccw(c2412.84,796.55) 2461.36,796.55 ccw(c2509.88,796.55) R29.1@2475.57,762.24 ; R29.1@2461.36,748.03 2461.36,1020.11 2555.19,1113.93 2555.19,1328.38 2652.39,1425.59 2652.39,1509.54 ; C24.1@2592.17,1557.62 2644.99,1557.62 ; C24.1@2602.01,1557.62 C24.1@2602.01,1542.53 2619.4,1542.53 2652.39,1509.54 ; C24.1@2608.25,1532.6 cw(c2614.45,1498.58) 2638.9,1523.03 ; C24.1@2610.04,1522.76 cw(c2618.61,1475.77) 2652.39,1509.55 ; C24.1@2616.5,1541.61 cw(c2634.03,1540.01) 2634.03,1557.62 ; C24.1@2626.45,1540.7 cw(c2644.99,1539.01) 2644.99,1557.62 ; C24.1@2626.54,1542.53 ccw(c2643.76,1542.53) 2631.58,1530.36 ; U1.11@2751.37,1670.82 cw(c2734.93,1670.82) 2746.56,1659.19 cw(c2758.18,1647.56) U1.11@2758.18,1664.01 ; U1.11@2778.37,1691 2644.99,1557.62
  Top Layer w15: R28.1@2382.62,748.03 R29.1@2461.36,748.03 ; R28.1@2399.5,735.59 cw(c2429.54,705.55) 2429.54,748.03 cw(c2429.54,790.52) R28.1@2399.5,760.48 ; R29.1@2444.49,735.59 ccw(c2414.45,705.55) 2414.45,748.03 ccw(c2414.45,790.52) R29.1@2444.49,760.48
PSU2_ADC_V: C21.1 R24.1 R26.1 U1.10 | length 1792.1
  Top Layer w10: R26.1@2292.62,761.26 ccw(c2258.31,795.57) 2306.84,795.57 ccw(c2355.36,795.57) R26.1@2321.05,761.26 ; R26.1@2306.84,747.05 2306.84,910.87 2528.68,1132.72 2528.68,1339.43 2472.68,1395.43 2472.68,1510.08 ; 2485.87,1523.28 cw(c2510.09,1499.06) C21.1@2516.85,1532.63 ; C21.1@2494.22,1531.63 ccw(c2483.32,1542.53) C21.1@2498.74,1542.53 ; C21.1@2514.88,1522.83 ccw(c2505.67,1477.09) 2472.68,1510.08 ; C21.1@2523.27,1542.53 C21.1@2513.43,1542.53 ; C21.1@2527.79,1542.57 cw(c2555.05,1553.04) 2534.4,1573.69 ; C21.1@2537.13,1546.16 cw(c2570.77,1559.08) 2545.29,1584.57 ; C21.1@2546.46,1549.74 cw(c2586.5,1565.13) 2556.17,1595.46 ; U1.10@2729.1,1693.09 cw(c2712.66,1693.09) 2724.29,1681.46 cw(c2735.91,1669.83) U1.10@2735.91,1686.28 ; U1.10@2756.1,1713.27 2638.28,1595.46 2556.17,1595.46 ; 2472.68,1510.08 2505.13,1542.53 C21.1@2513.43,1542.53 ; C21.1@2513.43,1542.53 2525.89,1555 2525.89,1565.18 2556.17,1595.46
  Top Layer w15: R24.1@2228.09,747.05 R26.1@2306.84,747.05 ; R24.1@2244.97,734.6 cw(c2275.01,704.56) 2275.01,747.05 cw(c2275.01,789.53) R24.1@2244.97,759.49 ; R26.1@2289.96,734.6 ccw(c2259.92,704.56) 2259.92,747.05 ccw(c2259.92,789.53) R26.1@2289.96,759.49
PSU2_DAC1: IC3.3 R10.2 U1.9 | length 1582.8
  Top Layer w10: v1@2467.62,1230.32 ccw(c2432.16,1230.32) 2457.23,1255.38 ccw(c2482.3,1280.45) v1@2482.3,1245 ; v1(2482.3,1230.32) 2429.36,1283.26 2429.36,1528.73 2524.08,1623.45 2621.73,1623.45 U1.9@2733.83,1735.54 ; U1.9@2706.83,1715.36 cw(c2690.39,1715.36) 2702.01,1703.73 cw(c2713.64,1692.11) U1.9@2713.64,1708.55
  Top Layer w15: v1@2627.95,1218.13 cw(c2627.95,1162.43) 2667.34,1201.82 ; v1(2627.95,1230.32) 2638.84,1230.32 2707.74,1161.42 R10.2@2888.92,1161.42 2889.91,1160.43 IC3.3@2889.91,1075.79 ; R10.2@2876.48,1144.54 cw(c2844.06,1112.13) 2889.91,1112.13 ; R10.2@2876.48,1148.97 ccw(c2846.44,1118.93) 2846.44,1161.42 ccw(c2846.44,1203.9) R10.2@2876.48,1173.86 ; 2889.91,1116.88 cw(c2929.03,1116.88) R10.2@2901.37,1144.54
  Bottom Layer w15: v1(2482.3,1230.32) v1(2627.95,1230.32) ; v1@2490.92,1221.7 cw(c2511.72,1200.9) 2511.72,1230.32 cw(c2511.72,1259.73) v1@2490.92,1238.93 ; v1@2619.34,1221.7 ccw(c2598.54,1200.9) 2598.54,1230.32 ccw(c2598.54,1259.73) v1@2619.34,1238.93
PSU2_ON/OFF: K7.1 Q2.D R17.1 | length 1365.7
  Top Layer w15: 2542.88,736.48 cw(c2566.26,713.1) R17.1@2582.53,741.89 ; 2556.84,750.44 cw(c2576.34,730.94) R17.1@2589.9,754.95 ; K7.1@2561.3,194.6 ccw(c2471.68,284.23) 2598.43,284.23 ccw(c2725.17,284.23) K7.1@2635.55,194.6 ; R17.1@2568.15,740.54 ccw(c2554.99,733.79) 2554.99,748.58 ; R17.1@2568.15,756.62 cw(c2554.99,763.38) 2554.99,748.58 ; R17.1@2571.81,765.89 ccw(c2546.17,793.44) 2583.8,793.44 ; K7.1@2571.91,184 ccw(c2507.89,248.01) 2598.43,248.01 ccw(c2688.96,248.01) K7.1@2624.94,184 ; R17.1@2575.15,728.83 ccw(c2556.19,695.26) 2528.92,722.52 ; R17.1@2595.79,765.89 cw(c2621.44,793.44) 2583.8,793.44 ; K7.1@2598.43,157.48 2598.43,511.2 2528.92,580.71 2528.92,722.52 ; Q2.D@2622.18,809.33 ccw(c2622.15,755.09) 2583.8,793.44 ; Q2.D@2622.19,831.83 2583.8,793.44 ; 2528.92,722.52 2554.98,748.58 ; 2554.98,748.58 R17.1@2583.8,748.58 2583.8,793.44
PSU2_OPAMP: K7.3 R9.2 | length 1373.9
  Top Layer w15: R9.2@2874.29,841.4 R9.2@2888.92,826.77 2813.98,826.77 2775.59,788.39 2775.59,591.57 2988.05,379.1 2988.05,161.55 K7.3@2992.13,157.48 K7.3@3021.65,187.01 ; R9.2@2876.48,814.33 ccw(c2846.44,784.29) 2846.44,826.77 ccw(c2846.44,869.26) R9.2@2876.48,839.22 ; K7.3@2955,194.6 ccw(c2875.21,274.4) 2988.05,274.4 ; K7.3@2965.61,184 ccw(c2911.42,238.18) 2988.05,238.18 ; 2988.05,221.63 ccw(c3056.28,221.63) K7.3@3008.04,173.39 ; 2988.05,257.84 ccw(c3092.49,257.84) K7.3@3018.64,184 ; 2988.05,294.06 ccw(c3128.7,294.06) K7.3@3029.25,194.6
QGND: C23.2 C25.1 NT2.1 | length 524.8
  Bottom Layer w18: v1(2267.76,2443.32) 2365.28,2443.32 ; v1@2275.31,2435.77 cw(c2293.55,2417.53) 2293.55,2443.32 cw(c2293.55,2469.12) v1@2275.31,2450.88
  Bottom Layer w19.68: 2365.28,2443.32 2434.18,2374.42 2434.18,2215.57 ; 2451.74,2334.85 NT2.1@2582.25,2334.85
pads on no net: K4.2 K7.2 K10.3 K10.4 U1.1 U1.2 U1.6 U1.7 U1.16 U1.17 U1.18 U1.19 U1.21 U1.22 U1.23 U1.26 U1.27 U1.28 U1.29 U1.30 U1.31 U1.32 U1.33 U1.36 U1.37 U1.38 U1.39 U1.40 U1.41 U1.46 U1.50 U1.51 U1.54 U1.55 U1.63 U1.64

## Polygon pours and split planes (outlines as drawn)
QGND on Bottom Layer "Top Layer-No Net" (solid, pour order 4): 1996.6,2205.13 2525.09,2205.13 2525.39,2204.83 2592.56,2272.91 2592.56,2274.84 2592.56,2410.67 2511.8,2492.53 2010.79,2492.53 1933.11,2413.79 1933.11,2269.49 1996.91,2204.83 2525.09,2204.83 2525.39,2205.13
GND on Bottom Layer "Top Layer-No Net" (solid, pour order 15): 3252.11,108.27 3252.11,334.65 1633.86,334.65 1633.86,108.27 2711.55,108.27
GND on Bottom Layer "Top Layer-No Net" (solid, pour order 17): 1309.06,108.27 1309.06,383.86 203.8,383.86 194.27,372.38 194.27,119.75 203.8,108.27 1137.55,108.27
24V_GND on Bottom Layer "Top Layer-No Net" (solid, pour order 25): 9.84,423.23 3454.72,423.23 3582.68,295.28 3582.68,9.84 9.84,9.84 9.84,423.23
24V_GND on Bottom Layer "Top Layer-No Net" (solid, pour order 29): 454.55,423.23 454.55,795.45 255.91,994.09 252.95,991.14 9.84,991.14 9.84,429.57 16.18,423.23 454.55,423.23
24V_GND on Bottom Layer "Top Layer-No Net" (solid, pour order 33): 16.18,991.14 16.18,1407.48 49.21,1407.48 49.21,1819.88 10.83,1819.88 9.84,1820.87 9.84,3218.5 915.35,3218.5 913.33,3216.48 913.33,3047.2 913.33,3019.99 895.31,3001.97 885.47,3011.81 541.34,3011.81 236.22,2706.69 236.22,991.14 16.18,991.14
12V on Bottom Layer "Top Layer-No Net" (solid, pour order 41): 1182.7,1899.61 1182.7,2616 1180.06,2618.11 364.17,2618.11 364.17,1899.61 1182.7,1899.61
5V on Bottom Layer "Top Layer-No Net" (solid, pour order 43): 1123.73,1122.05 1123.73,1760.27 1122.05,1761.81 1119.22,1759.22 364.17,1759.22 364.17,1122.05
3.3V on Bottom Layer "Top Layer-No Net" (solid, pour order 45): 1131.89,1122.05 1836.04,1122.05 1899.61,1180 1899.61,1184.36 1899.61,1758.31 1898.6,1759.22 1131.89,1759.22 1131.89,1122.05
GND on Bottom Layer "Top Layer-No Net" (solid, remove dead copper, pour order 55): 0,3228.35 3858.27,3228.35 3858.27,1811.02 3818.9,1811.02 3818.9,1417.32 3858.27,1417.32 3858.27,9.84 3848.43,0 0,0 0,1417.32 39.37,1417.32 39.37,1811.02 0,1811.02 0,3228.35
QGND on Top Layer "Top Layer-No Net" (solid, pour order 2): 2039.79,2204.83 2524.68,2204.83 2524.68,2205.13 2592.56,2274.03 2591.76,2274.84 2591.76,2410.67 2511.1,2492.53 2010.69,2492.53 1933.11,2413.79 1933.11,2276 1933.11,2269.49 1992.65,2209.07 1996.83,2204.83 2001,2204.83
3.3V on Top Layer "Top Layer-No Net" (solid, pour order 6): 2583.5,1961.04 2937.05,2314.59 3290.6,1961.04 2937.05,1607.48 2583.5,1961.04 2652.39,2029.94
3.3V on Top Layer "Top Layer-No Net" (solid, pour order 35): 1177.03,1759.22 1178.5,1757.79 1899.61,1757.79 1899.61,1184.22 1836.04,1122.05 1131.89,1122.05 1131.89,1757.79 1177.03,1757.79 1186.06,1757.79
5V on Top Layer "Top Layer-No Net" (solid, pour order 37): 1131.89,1122.05 1131.89,1761.81 367.35,1761.81 364.17,1759.22 364.17,1122.05 1131.89,1122.05
GND on Top Layer "Top Layer-No Net" (solid, remove dead copper, pour order 53): 0,3228.35 3858.27,3228.35 3858.27,1811.02 3818.9,1811.02 3818.9,1417.32 3858.27,1417.32 3858.27,0 0,0 0,1417.32 39.37,1417.32 39.37,1811.02 0,1811.02 0,3228.35
12V on Top Layer "Top Layer-No Net" (solid, pour order 39): 367.35,1899.61 1182.7,1899.61 1182.7,2615.86 1183.32,2616.51 1182.38,2617.49 367.35,2617.49

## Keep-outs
Keep-Out Layer:
  lines w7.87: 196.85,3228.35 112.6,3228.35 0,3228.35 0,3025.5 0,1869.17 39.37,1829.8 39.37,1398.76 0,1359.39 0,1269.68 0,0 3779.53,0 3779.53,3166.01 1011.71,3166.01 949.37,3228.35 196.85,3228.35 ; 196.85,3228.35 196.85,3228.35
